One B-rep face of a CAD part: STEP entity #157.
In plain terms, the planar face has unit normal (1, 0, 0).
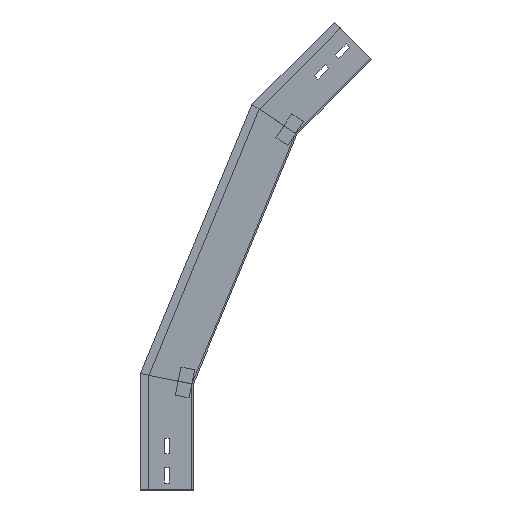
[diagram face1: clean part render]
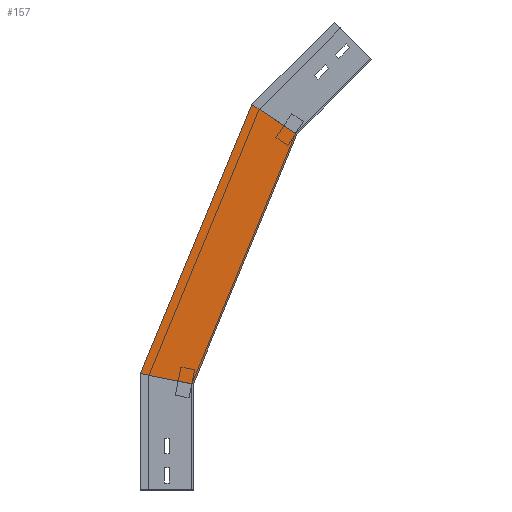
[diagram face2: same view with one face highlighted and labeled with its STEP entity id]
Its self-contained STEP definition (entity closure, numbers rounded to 3 decimals):
#22 = CARTESIAN_POINT ( 'NONE',  ( 0., 75., 164.918 ) ) ;
#96 = ORIENTED_EDGE ( 'NONE', *, *, #467, .F. ) ;
#132 = VERTEX_POINT ( 'NONE', #957 ) ;
#157 = ADVANCED_FACE ( 'NONE', ( #1191 ), #648, .T. ) ;
#159 = DIRECTION ( 'NONE',  ( 0., -0.831, -0.556 ) ) ;
#174 = DIRECTION ( 'NONE',  ( 0., 0., -1. ) ) ;
#200 = CARTESIAN_POINT ( 'NONE',  ( 0., 75.609, 163.448 ) ) ;
#277 = EDGE_CURVE ( 'NONE', #1212, #132, #451, .T. ) ;
#289 = DIRECTION ( 'NONE',  ( 0., -0.383, 0.924 ) ) ;
#311 = VECTOR ( 'NONE', #159, 1000. ) ;
#315 = DIRECTION ( 'NONE',  ( 0., -0.383, 0.924 ) ) ;
#323 = DIRECTION ( 'NONE',  ( 0., -0.981, -0.195 ) ) ;
#389 = DIRECTION ( 'NONE',  ( 1., 0., 0. ) ) ;
#405 = CARTESIAN_POINT ( 'NONE',  ( 0., 6.318, 134.746 ) ) ;
#419 = VERTEX_POINT ( 'NONE', #1111 ) ;
#421 = VERTEX_POINT ( 'NONE', #1159 ) ;
#451 = LINE ( 'NONE', #200, #1168 ) ;
#454 = EDGE_LOOP ( 'NONE', ( #969, #951, #96, #1361 ) ) ;
#467 = EDGE_CURVE ( 'NONE', #421, #419, #742, .T. ) ;
#541 = LINE ( 'NONE', #1195, #311 ) ;
#646 = LINE ( 'NONE', #984, #992 ) ;
#648 = PLANE ( 'NONE',  #873 ) ;
#682 = VECTOR ( 'NONE', #289, 1000. ) ;
#742 = LINE ( 'NONE', #747, #682 ) ;
#747 = CARTESIAN_POINT ( 'NONE',  ( 0., 6.318, 134.746 ) ) ;
#873 = AXIS2_PLACEMENT_3D ( 'NONE', #405, #389, #174 ) ;
#951 = ORIENTED_EDGE ( 'NONE', *, *, #1349, .T. ) ;
#957 = CARTESIAN_POINT ( 'NONE',  ( 0., -82.986, 546.33 ) ) ;
#969 = ORIENTED_EDGE ( 'NONE', *, *, #277, .T. ) ;
#984 = CARTESIAN_POINT ( 'NONE',  ( 0., -28.701, 144.291 ) ) ;
#992 = VECTOR ( 'NONE', #323, 1000. ) ;
#1090 = EDGE_CURVE ( 'NONE', #1212, #421, #646, .T. ) ;
#1111 = CARTESIAN_POINT ( 'NONE',  ( 0., -146.568, 503.846 ) ) ;
#1159 = CARTESIAN_POINT ( 'NONE',  ( 0., 0., 150. ) ) ;
#1168 = VECTOR ( 'NONE', #315, 1000. ) ;
#1191 = FACE_OUTER_BOUND ( 'NONE', #454, .T. ) ;
#1195 = CARTESIAN_POINT ( 'NONE',  ( 0., -211.373, 460.544 ) ) ;
#1212 = VERTEX_POINT ( 'NONE', #22 ) ;
#1349 = EDGE_CURVE ( 'NONE', #132, #419, #541, .T. ) ;
#1361 = ORIENTED_EDGE ( 'NONE', *, *, #1090, .F. ) ;
